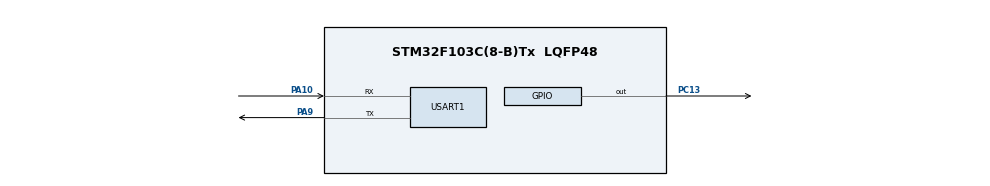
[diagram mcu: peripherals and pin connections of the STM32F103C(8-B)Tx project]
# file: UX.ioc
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Mcu.Family=STM32F1
Mcu.Name=STM32F103C(8-B)Tx
Mcu.Package=LQFP48
NVIC.PriorityGroup=NVIC_PRIORITYGROUP_4
PA10.Mode=Asynchronous
PA10.Signal=USART1_RX
PA13.Mode=Serial_Wire
PA13.Signal=SYS_JTMS-SWDIO
PA14.Mode=Serial_Wire
PA14.Signal=SYS_JTCK-SWCLK
PA9.Mode=Asynchronous
PA9.Signal=USART1_TX
PC13-TAMPER-RTC.Signal=GPIO_Output
PD0-OSC_IN.Mode=HSE-External-Oscillator
PD0-OSC_IN.Signal=RCC_OSC_IN
PD1-OSC_OUT.Mode=HSE-External-Oscillator
PD1-OSC_OUT.Signal=RCC_OSC_OUT
ProjectManager.HeapSize=0x200
ProjectManager.StackSize=0x400
ProjectManager.TargetToolchain=MDK-ARM V5.32
RCC.APB1Freq_Value=8000000
RCC.APB2Freq_Value=8000000
USART1.VirtualMode=VM_ASYNC
board=custom

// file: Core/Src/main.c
/* USER CODE END Header */
#include "main.h"
#include "gpio.h"
#include "usart.h"
/* USER CODE BEGIN Includes */
#include <includes.h>
#include "stm32f1xx_hal.h"
/* USER CODE END Includes */

/* USER CODE BEGIN PD */
/* 任务优先级 */
#define START_TASK_PRIO		3
#define LED0_TASK_PRIO		4
#define MSG_TASK_PRIO		5
#define LED1_TASK_PRIO		6

/* 任务堆栈大小	*/
#define START_STK_SIZE 		96
#define LED0_STK_SIZE 		64
#define MSG_STK_SIZE 		64
#define LED1_STK_SIZE 		64

/* 任务栈 */
CPU_STK START_TASK_STK[START_STK_SIZE];
CPU_STK LED0_TASK_STK[LED0_STK_SIZE];
CPU_STK MSG_TASK_STK[MSG_STK_SIZE];
CPU_STK LED1_TASK_STK[LED1_STK_SIZE];

/* 任务控制块 */
OS_TCB StartTaskTCB;
OS_TCB Led0TaskTCB;
OS_TCB MsgTaskTCB;
OS_TCB Led1TaskTCB;

/* USER CODE END PD */

/* USER CODE BEGIN PV */

/* 任务函数定义 */
void start_task(void *p_arg);
static  void  AppTaskCreate(void);
static  void  AppObjCreate(void);
static  void  led_pc13(void *p_arg);
static  void  send_msg(void *p_arg);
static  void  led_pa3(void *p_arg);
/* USER CODE END PV */

void SystemClock_Config(void);

/* USER CODE BEGIN 0 */
/**
  * @brief System Clock Configuration
  * @retval None
  */
  /* USER CODE BEGIN 1 */

typedef struct __FILE FILE;
int fputc(int ch,FILE *f){
	HAL_UART_Transmit(&huart1,(uint8_t *)&ch,1,0xffff);
	return ch;
}
/* USER CODE END 1 */

void SystemClock_Config(void)
{
  RCC_OscInitTypeDef RCC_OscInitStruct = {0};
  RCC_ClkInitTypeDef RCC_ClkInitStruct = {0};

  /**Initializes the CPU, AHB and APB busses clocks
  */
  RCC_OscInitStruct.OscillatorType = RCC_OSCILLATORTYPE_HSE;
  RCC_OscInitStruct.HSEState = RCC_HSE_ON;
  RCC_OscInitStruct.HSEPredivValue = RCC_HSE_PREDIV_DIV1;
  RCC_OscInitStruct.HSIState = RCC_HSI_ON;
  RCC_OscInitStruct.PLL.PLLState = RCC_PLL_ON;
  RCC_OscInitStruct.PLL.PLLSource = RCC_PLLSOURCE_HSE;
  RCC_OscInitStruct.PLL.PLLMUL = RCC_PLL_MUL9;
  if (HAL_RCC_OscConfig(&RCC_OscInitStruct) != HAL_OK)
  {
    Error_Handler();
  }
  /**Initializes the CPU, AHB and APB busses clocks
  */
  RCC_ClkInitStruct.ClockType = RCC_CLOCKTYPE_HCLK|RCC_CLOCKTYPE_SYSCLK
                              |RCC_CLOCKTYPE_PCLK1|RCC_CLOCKTYPE_PCLK2;
  RCC_ClkInitStruct.SYSCLKSource = RCC_SYSCLKSOURCE_PLLCLK;
  RCC_ClkInitStruct.AHBCLKDivider = RCC_SYSCLK_DIV1;
  RCC_ClkInitStruct.APB1CLKDivider = RCC_HCLK_DIV2;
  RCC_ClkInitStruct.APB2CLKDivider = RCC_HCLK_DIV1;

  if (HAL_RCC_ClockConfig(&RCC_ClkInitStruct, FLASH_LATENCY_2) != HAL_OK)
  {
    Error_Handler();
  }
}

/* USER CODE END 0 */

int main(void)
{
	OS_ERR  err;
	OSInit(&err);
  HAL_Init();
	SystemClock_Config();
	//MX_GPIO_Init(); 这个在BSP的初始化里也会初始化
  MX_USART1_UART_Init();
	/* 创建任务 */
	OSTaskCreate((OS_TCB     *)&StartTaskTCB,                /* Create the start task                                */
				 (CPU_CHAR   *)"start task",
				 (OS_TASK_PTR ) start_task,
				 (void       *) 0,
				 (OS_PRIO     ) START_TASK_PRIO,
				 (CPU_STK    *)&START_TASK_STK[0],
				 (CPU_STK_SIZE) START_STK_SIZE/10,
				 (CPU_STK_SIZE) START_STK_SIZE,
				 (OS_MSG_QTY  ) 0,
				 (OS_TICK     ) 0,
				 (void       *) 0,
				 (OS_OPT      )(OS_OPT_TASK_STK_CHK | OS_OPT_TASK_STK_CLR),
				 (OS_ERR     *)&err);
	/* 启动多任务系统，控制权交给uC/OS-III */
	OSStart(&err);            /* Start multitasking (i.e. give control to uC/OS-III). */

}

void start_task(void *p_arg)
{
	OS_ERR err;
	CPU_SR_ALLOC();
	p_arg = p_arg;

	/* YangJie add 2021.05.20*/
  BSP_Init();                                                   /* Initialize BSP functions */
  //CPU_Init();
  //Mem_Init();                                                 /* Initialize Memory Management Module */

#if OS_CFG_STAT_TASK_EN > 0u
   OSStatTaskCPUUsageInit(&err);  		//统计任务
#endif

#ifdef CPU_CFG_INT_DIS_MEAS_EN			//如果使能了测量中断关闭时间
    CPU_IntDisMeasMaxCurReset();
#endif

#if	OS_CFG_SCHED_ROUND_ROBIN_EN  		//当使用时间片轮转的时候
	 //使能时间片轮转调度功能,时间片长度为1个系统时钟节拍，既1*5=5ms
	OSSchedRoundRobinCfg(DEF_ENABLED,1,&err);
#endif

	OS_CRITICAL_ENTER();	//进入临界区
	/* 创建LED0任务 */
	OSTaskCreate((OS_TCB 	* )&Led0TaskTCB,
				 (CPU_CHAR	* )"led_pc13",
                 (OS_TASK_PTR )led_pc13,
                 (void		* )0,
                 (OS_PRIO	  )LED0_TASK_PRIO,
                 (CPU_STK   * )&LED0_TASK_STK[0],
                 (CPU_STK_SIZE)LED0_STK_SIZE/10,
                 (CPU_STK_SIZE)LED0_STK_SIZE,
                 (OS_MSG_QTY  )0,
                 (OS_TICK	  )0,
                 (void   	* )0,
                 (OS_OPT      )OS_OPT_TASK_STK_CHK|OS_OPT_TASK_STK_CLR,
                 (OS_ERR 	* )&err);

/* 创建LED1任务 */
	OSTaskCreate((OS_TCB 	* )&Led1TaskTCB,
				 (CPU_CHAR	* )"led_pa3",
                 (OS_TASK_PTR )led_pa3,
                 (void		* )0,
                 (OS_PRIO	  )LED1_TASK_PRIO,
                 (CPU_STK   * )&LED1_TASK_STK[0],
                 (CPU_STK_SIZE)LED1_STK_SIZE/10,
                 (CPU_STK_SIZE)LED1_STK_SIZE,
                 (OS_MSG_QTY  )0,
                 (OS_TICK	  )0,
                 (void   	* )0,
                 (OS_OPT      )OS_OPT_TASK_STK_CHK|OS_OPT_TASK_STK_CLR,
                 (OS_ERR 	* )&err);

	/* 创建MSG任务 */
	OSTaskCreate((OS_TCB 	* )&MsgTaskTCB,
				 (CPU_CHAR	* )"send_msg",
                 (OS_TASK_PTR )send_msg,
                 (void		* )0,
                 (OS_PRIO	  )MSG_TASK_PRIO,
                 (CPU_STK   * )&MSG_TASK_STK[0],
                 (CPU_STK_SIZE)MSG_STK_SIZE/10,
                 (CPU_STK_SIZE)MSG_STK_SIZE,
                 (OS_MSG_QTY  )0,
                 (OS_TICK	  )0,
                 (void   	* )0,
                 (OS_OPT      )OS_OPT_TASK_STK_CHK|OS_OPT_TASK_STK_CLR,
                 (OS_ERR 	* )&err);

	OS_TaskSuspend((OS_TCB*)&StartTaskTCB,&err);		//挂起开始任务
	OS_CRITICAL_EXIT();	//进入临界区
}
/**
  * 函数功能: 启动任务函数体。
  * 输入参数: p_arg 是在创建该任务时传递的形参
  * 返 回 值: 无
  * 说    明：无
  */
static  void  led_pc13 (void *p_arg)
{
  OS_ERR      err;

  (void)p_arg;

  BSP_Init();                                                 /* Initialize BSP functions                             */
  CPU_Init();

  Mem_Init();                                                 /* Initialize Memory Management Module                  */

#if OS_CFG_STAT_TASK_EN > 0u
  OSStatTaskCPUUsageInit(&err);                               /* Compute CPU capacity with no task running            */
#endif

  CPU_IntDisMeasMaxCurReset();

  AppTaskCreate();                                            /* Create Application Tasks                             */

  AppObjCreate();                                             /* Create Application Objects                           */

  while (DEF_TRUE)
  {
		HAL_GPIO_WritePin(GPIOC,GPIO_PIN_13,GPIO_PIN_RESET);
		OSTimeDlyHMSM(0, 0, 1, 0,OS_OPT_TIME_HMSM_STRICT,&err);
		HAL_GPIO_WritePin(GPIOC,GPIO_PIN_13,GPIO_PIN_SET);
		OSTimeDlyHMSM(0, 0, 1, 0,OS_OPT_TIME_HMSM_STRICT,&err);
    /* USER CODE END WHILE */

  }
}

static  void  led_pa3 (void *p_arg)
{
  OS_ERR      err;

  (void)p_arg;

  BSP_Init();                                                 /* Initialize BSP functions                             */
  CPU_Init();

  Mem_Init();                                                 /* Initialize Memory Management Module                  */

#if OS_CFG_STAT_TASK_EN > 0u
  OSStatTaskCPUUsageInit(&err);                               /* Compute CPU capacity with no task running            */
#endif

  CPU_IntDisMeasMaxCurReset();

  AppTaskCreate();                                            /* Create Application Tasks                             */

  AppObjCreate();                                             /* Create Application Objects                           */

  while (DEF_TRUE)
  {
		HAL_GPIO_WritePin(GPIOA,GPIO_PIN_3,GPIO_PIN_RESET);
		OSTimeDlyHMSM(0, 0, 3, 0,OS_OPT_TIME_HMSM_STRICT,&err);
		HAL_GPIO_WritePin(GPIOA,GPIO_PIN_3,GPIO_PIN_SET);
		OSTimeDlyHMSM(0, 0, 3, 0,OS_OPT_TIME_HMSM_STRICT,&err);
    /* USER CODE END WHILE */

  }
}

static  void  send_msg (void *p_arg)
{
  OS_ERR      err;

  (void)p_arg;

  BSP_Init();                                                 /* Initialize BSP functions                             */
  CPU_Init();

  Mem_Init();                                                 /* Initialize Memory Management Module                  */

#if OS_CFG_STAT_TASK_EN > 0u
  OSStatTaskCPUUsageInit(&err);                               /* Compute CPU capacity with no task running            */
#endif

  CPU_IntDisMeasMaxCurReset();

  AppTaskCreate();                                            /* Create Application Tasks                             */

  AppObjCreate();                                             /* Create Application Objects                           */

  while (DEF_TRUE)
  {
			printf("hello uc/OS \r\n");
		OSTimeDlyHMSM(0, 0, 2, 0,OS_OPT_TIME_HMSM_STRICT,&err);
    /* USER CODE END WHILE */

  }
}

/* USER CODE BEGIN 4 */
/**
  * 函数功能: 创建应用任务
  * 输入参数: p_arg 是在创建该任务时传递的形参
  * 返 回 值: 无
  * 说    明：无
  */
static  void  AppTaskCreate (void)
{

}

/**
  * 函数功能: uCOSIII内核对象创建
  * 输入参数: 无
  * 返 回 值: 无
  * 说    明：无
  */
static  void  AppObjCreate (void)
{

}

/* USER CODE END 4 */

void Error_Handler(void)
{
}

/************************ (C) COPYRIGHT STMicroelectronics *****END OF FILE****/
